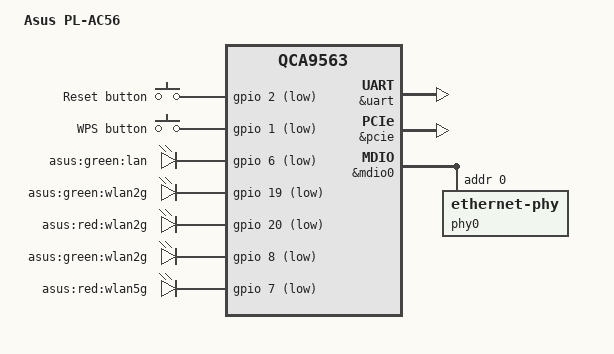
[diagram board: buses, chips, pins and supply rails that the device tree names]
// SPDX-License-Identifier: GPL-2.0-or-later OR MIT

#include <dt-bindings/gpio/gpio.h>
#include <dt-bindings/input/input.h>

#include "qca956x.dtsi"

/ {
	compatible = "asus,pl-ac56", "qca,qca9563";
	model = "Asus PL-AC56";

	chosen {
		bootargs = "console=ttyS0,115200n8";

	keys {
		compatible = "gpio-keys";
		#address-cells = <1>;
		#size-cells = <0>;

		reset {
			label = "Reset button";
			linux,code = <KEY_RESTART>;
			gpios = <&gpio 2 GPIO_ACTIVE_LOW>;
			debounce-interval = <60>;
		};

		wps {
			label = "WPS button";
			linux,code = <KEY_WPS_BUTTON>;
			gpios = <&gpio 1 GPIO_ACTIVE_LOW>;
			debounce-interval = <60>;
		};
	};

	leds {
		compatible = "gpio-leds";

		lan {
			label = "asus:green:lan";
			gpios = <&gpio 6 GPIO_ACTIVE_LOW>;
			default-state = "off";
			linux,default-trigger = "phy0tpt";
		};

		wlan_2g_green {
			label = "asus:green:wlan2g";
			gpios = <&gpio 19 GPIO_ACTIVE_LOW>;
			default-state = "off";
			linux,default-trigger = "phy0tpt";
		};

		wlan_2g_red {
			label = "asus:red:wlan2g";
			gpios = <&gpio 20 GPIO_ACTIVE_LOW>;
			default-state = "off";
		};
		
		wlan_5g_green {
			label = "asus:green:wlan2g";
			gpios = <&gpio 8 GPIO_ACTIVE_LOW>;
			default-state = "off";
			linux,default-trigger = "phy1tpt";
		};

		wlan_5g_red {
			label = "asus:red:wlan5g";
			gpios = <&gpio 7 GPIO_ACTIVE_LOW>;
			default-state = "off";
		};
	};
};

&uart {
	status = "okay";
};

&gpio {
	status = "okay";
};

&pcie {
	status = "okay";
};

&mdio0 {
	status = "okay";

	phy-mask = <0>;
	phy0: ethernet-phy@0 {
		reg = <0>;
		phy-mode = "rgmii";

		qca,ar8327-initvals = <
			0x0004 0x80080080 /* PAD0_MODE */
			0x0008 0x01000000 /* PAD5_MODE */
			0x000c 0x07600000 /* PAD6_MODE */
			0x0010 0x602613a0 /* POWER_ON_STRIP */
			0x0050 0xcc35cc35 /* LED_CTRL0 */
			0x0054 0xca35ca35 /* LED_CTRL1 */
			0x0058 0xc935c935 /* LED_CTRL2 */
			0x005c 0x03ffff00 /* LED_CTRL3 */
			0x007c 0x000000fe /* PORT0_STATUS */
			0x0094 0x0000070e /* PORT6_STATUS */
		>;
	};

&wmac {
	status = "disabled";
	mtd-mac-address = <&art 0x0>;
	mtd-cal-data = <&art 0x1000>;
};
